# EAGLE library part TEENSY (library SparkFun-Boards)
Teensy Footprint Mechanical footprint with connectors for Teensy Development Board with ARM Cortex. SparkFun Products: Teensy 4.0 Teensy 4.0 (with Headers) Teensy 3.2 Teensy LC SparkFun Qwiic Shield for Teensy Teensy Header Kit

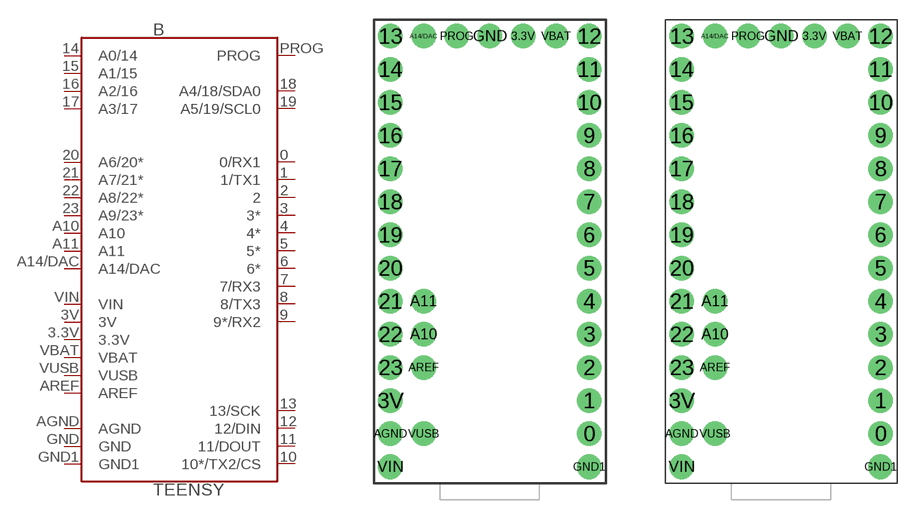
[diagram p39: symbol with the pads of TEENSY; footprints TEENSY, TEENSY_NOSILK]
Designator prefix B

## TEENSYSILK (SF_ID: DEV-12646)  [TEENSY]
0  0/RX1
1  1/TX1
2  2
3  3*
3.3V  3.3V  pwr
3V  3V  pwr
4  4*
5  5*
6  6*
7  7/RX3
8  8/TX3
9  9*/RX2
10  10*/TX2/CS
11  11/DOUT
12  12/DIN
13  13/SCK
14  A0/14
15  A1/15
16  A2/16
17  A3/17
18  A4/18/SDA0
19  A5/19/SCL0
20  A6/20*
21  A7/21*
22  A8/22*
23  A9/23*
A10  A10
A11  A11
A14/DAC  A14/DAC
AGND  AGND  pwr
AREF  AREF
GND  GND  pwr
GND1  GND1  pwr
PROG  PROG
VBAT  VBAT  pwr
VIN  VIN  pwr
VUSB  VUSB  pwr

## TEENSYNOSILK (SF_ID: DEV-12646)  [TEENSY_NOSILK]
Pads as for TEENSY

## Footprint TEENSY (pad centres in mm)
Teensy 3 Footprint Specifications: Pin count:37 Pin pitch: 0.1" Area:0.7x1.4" Example device(s): Teensy 3.1
drill 1.016 pad 1.88: 0 7.62,-13.97; 1 7.62,-11.43; 2 7.62,-8.89; 3 7.62,-6.35; 3.3V 2.54,16.51; 3V -7.62,-11.43; 4 7.62,-3.81; 5 7.62,-1.27; 6 7.62,1.27; 7 7.62,3.81; 8 7.62,6.35; 9 7.62,8.89; 10 7.62,11.43; 11 7.62,13.97; 12 7.62,16.51; 13 -7.62,16.51; 14 -7.62,13.97; 15 -7.62,11.43; 16 -7.62,8.89; 17 -7.62,6.35; 18 -7.62,3.81; 19 -7.62,1.27; 20 -7.62,-1.27; 21 -7.62,-3.81; 22 -7.62,-6.35; 23 -7.62,-8.89; A10 -5.08,-6.35; A11 -5.08,-3.81; A14/DAC -5.08,16.51; AGND -7.62,-13.97; AREF -5.08,-8.89; GND 0,16.51; GND1 7.62,-16.51; PROG -2.54,16.51; VBAT 5.08,16.51; VIN -7.62,-16.51; VUSB -5.08,-13.97

## Footprint TEENSY_NOSILK (pad centres in mm)
Teensy 3 Footprint- No Silk Label on Pins Specifications: Pin count:37 Pin pitch: 0.1" Area:0.7x1.4" Example device(s): Teensy 3.1
drill 1.016 pad 1.88: 0 7.62,-13.97; 1 7.62,-11.43; 2 7.62,-8.89; 3 7.62,-6.35; 3.3V 2.54,16.51; 3V -7.62,-11.43; 4 7.62,-3.81; 5 7.62,-1.27; 6 7.62,1.27; 7 7.62,3.81; 8 7.62,6.35; 9 7.62,8.89; 10 7.62,11.43; 11 7.62,13.97; 12 7.62,16.51; 13 -7.62,16.51; 14 -7.62,13.97; 15 -7.62,11.43; 16 -7.62,8.89; 17 -7.62,6.35; 18 -7.62,3.81; 19 -7.62,1.27; 20 -7.62,-1.27; 21 -7.62,-3.81; 22 -7.62,-6.35; 23 -7.62,-8.89; A10 -5.08,-6.35; A11 -5.08,-3.81; A14/DAC -5.08,16.51; AGND -7.62,-13.97; AREF -5.08,-8.89; GND 0,16.51; GND1 7.62,-16.51; PROG -2.54,16.51; VBAT 5.08,16.51; VIN -7.62,-16.51; VUSB -5.08,-13.97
